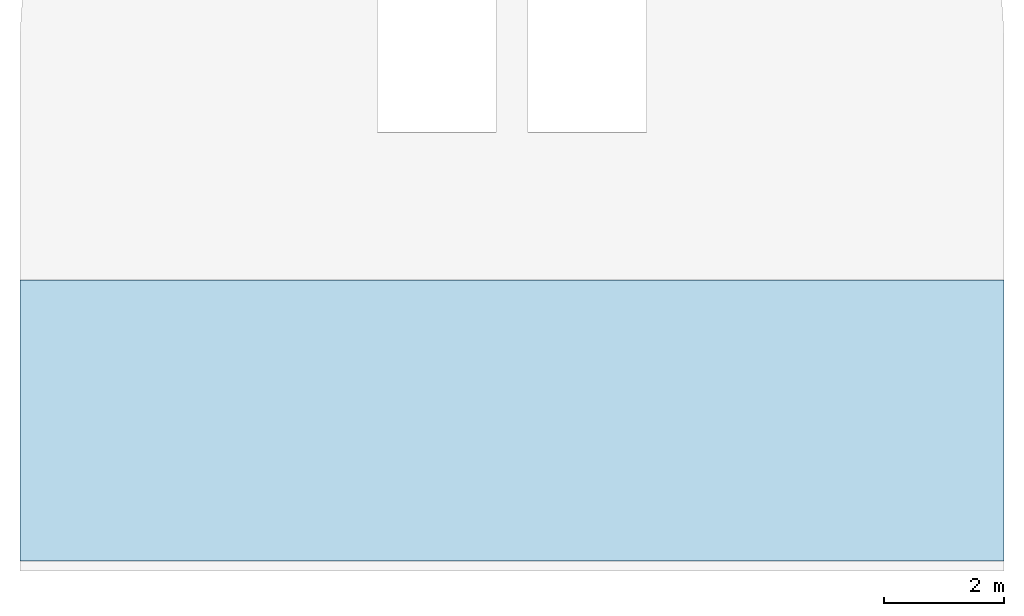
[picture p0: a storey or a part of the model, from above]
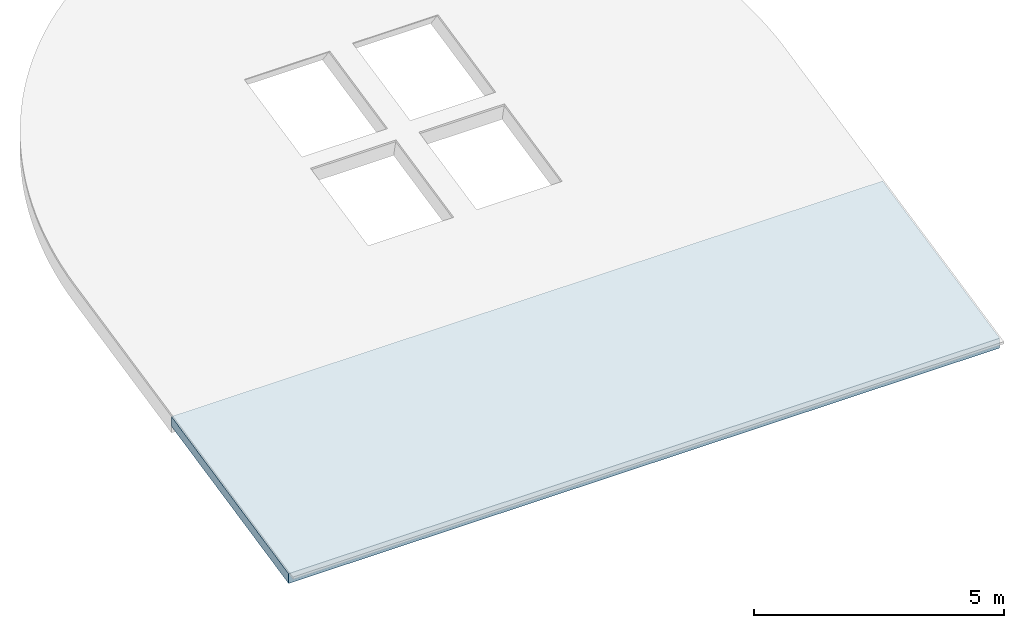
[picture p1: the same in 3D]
Properties of the parts of a building model (IFC4)

# File
Description: ViewDefinition [Design_Transfer_View, QuantityTakeOffAddOnView, SpaceBoundary2ndLevelAddOnView], ExchangeRequirement [Architecture], Option [Elements to export: Visible elements (on all stories)], Option [Partial Structure Display: Entire Model], Option [IFC Domain: All], Option [Structural Function: All Elements], Option [Convert Grid elements: On], Option [Convert IFC Annotations and Archicad 2D elements: Off], Option [Convert 2D symbols of Doors and Windows: Off], Option [Export geometries that Participates in Collision Detection only: Off], Option [Split complex elements: Off], Option [Material Preservation: Explode where necessary], Option [Elements in Solid Element Operations: Extruded/revolved], Option [Elements with junctions: Extruded/revolved without junctions], Option [IFC Model position: Survey Point and Project Origin], Option [Curtain Wall export mode: Container Element], Option [Railing export mode: Single Element], Option [Stair export mode: Container Element], Option [Properties To Export: All properties], Option [Space containment: On], Option [IFC Domain For Space Containment: All], Option [Geometry to type objects: Off], Option [Element Properties: Off], Option [Building Material Properties: Off], Option [Element Parameters: Off], Option [Component Parameters: Off], Option [IFC Base Quantities: On], Option [Door Window Parameters: On], Option [IFC Space boundaries: On], Option [Archicad Zone Categories as IFC Space classification data: Off], Option [Element Classifications: Off]
File name: C:\Users\micel\OneDrive\Dokumenty\ŠKOLA\!!4.LS!!\BAKALÁŘKA\Publikace\Nová složka\_LES24-PST-XX-M3-Nosna_kce_strech.ifc
Time: 2024-05-21T14:07:18
Author: Architect
Organization: Building Designer Office
Written by: DDS_IFC v3.0
Made in: IFC file generated by Graphisoft Archicad 27.0.0 CZE FULL Windows version (IFC add-on version: 3001 CZE FULL).
Authorization: The authorising person

# IfcProject, Univerzitní lezecké centrum
Description: BIM projekt - bakalářská práce

# IfcSite, Exteriér
RefLatitude: 50, 1, 18, 339575; RefLongitude: 15, 46, 11, 568244; RefElevation: 221783 mm
Qto_SiteBaseQuantities - GrossPerimeter: 0 mm; GrossArea: 3562 m2

# IfcBuilding, Univerzitní lezecké centrum
Qto_BuildingBaseQuantities - GrossFloorArea: 0 m2

# IfcBuildingStorey, Střecha
In: Univerzitní lezecké centrum
Elevation: 12800 mm
Qto_BuildingStoreyBaseQuantities - NetHeight: 8000 mm; GrossHeight: 8000 mm; GrossFloorArea: 0 m2

# IfcSlab: Ocelový válcovaný I profil 235, NS01
In: Střecha
Type - PredefinedType: ROOF
Material: Ocelový válcovaný I profil 234.755 mm
Pset_SlabCommon - Status: EXISTING; LoadBearing: yes
Pset_ManufacturerOccurrence - AcquisitionDate: DD.MM.RRRR
Qto_SlabBaseQuantities - Width: 234.755 mm; Perimeter: 42367.7 mm; GrossArea: 78.4548 m2; NetArea: 78.4548 m2; GrossVolume: 18.4177 m3; NetVolume: 18.4177 m3; Ocelový válcovaný I profil, Width: 234.755 mm

# IfcSlab: Ocelový válcovaný I profil 391, NS01
In: Střecha
Type - PredefinedType: ROOF
Material: Ocelový válcovaný I profil
Qto_SlabBaseQuantities - Width: 391.259 mm; Perimeter: 50325.7 mm; GrossArea: 153.738 m2; NetArea: 153.738 m2; GrossVolume: 59.8694 m3; NetVolume: 59.8694 m3; Ocelový válcovaný I profil, Width: 391.259 mm
Pset_ManufacturerOccurrence - AcquisitionDate: DD.MM.RRRR
Pset_SlabCommon - Status: EXISTING; LoadBearing: yes

# IfcSlab: Trapézový plech 54, S01
In: Střecha
Type - PredefinedType: ROOF
Material: Trapézový plech
Pset_SlabCommon - Status: EXISTING; LoadBearing: yes
Pset_ManufacturerOccurrence - AcquisitionDate: DD.MM.RRRR
Qto_SlabBaseQuantities - Width: 53.7981 mm; Perimeter: 60241 mm; GrossArea: 235.241 m2; NetArea: 235.241 m2; GrossVolume: 12.6502 m3; NetVolume: 12.6502 m3; Trapézový plech, Width: 53.7981 mm
